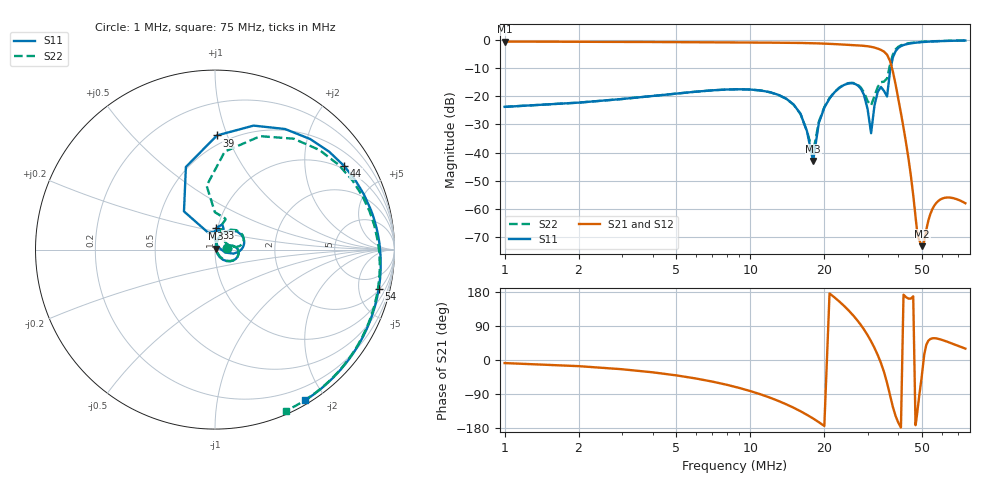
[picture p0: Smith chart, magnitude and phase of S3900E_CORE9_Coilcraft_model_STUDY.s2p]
! Simulated 50-ohm nominal data; not measured. Coilcraft 0805CS fitted passive equivalent + C0G tanD assumed.
# Hz S RI R 50
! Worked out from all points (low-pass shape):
!   277 points, 1 MHz to 75 MHz, reference 50 ohm
!   highest |S21| = -0.56 dB at 1 MHz (marker M1); lowest = -73.2 dB at 50 MHz (marker M2)
!   |S21| within 3 dB of the highest: start of sweep to 34.07 MHz
!   lowest |S11| = -43.0 dB at 18 MHz (marker M3), VSWR 1.01, Z = 50.5 + j0.514 ohm
!   |S11| at or under -10 dB: start of sweep to 37.25 MHz
!   |S22| runs from -40.1 to -0.2 dB; largest |S21 - S12| = 0
!   S11 on the Smith chart (normalised r, x): 1 MHz: 1.14, +0.02; 33 MHz: 0.99, +0.24; 39 MHz: 0.43, +0.92; 44 MHz: 0.89, +3.15; 54 MHz: 2.19, -7.93; 75 MHz: 0.04, -1.76
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1000000  0.0642 0.01  0.928 -0.1323  0.928 -0.1323  0.0642 0.01
3000000  0.087 0.0208  0.8431 -0.3813  0.8431 -0.3813  0.087 0.0208
5000000  0.1104 0.0175  0.6961 -0.5965  0.6961 -0.5965  0.1104 0.0176
9000000  0.131 -0.0258  0.2552 -0.8673  0.2552 -0.8673  0.131 -0.0252
1.5e7  0.0441 -0.0561  -0.5227 -0.7195  -0.5227 -0.7195  0.0458 -0.0542
1.7e7  0.0122 -0.0206  -0.7193 -0.5094  -0.7193 -0.5094  0.0147 -0.0189
1.8e7  0.00492 0.00509  -0.7896 -0.3797  -0.7896 -0.3797  0.00752 0.00646
1.9e7  0.00591 0.0332  -0.8367 -0.2378  -0.8367 -0.2378  0.00827 0.0343
2.2e7  0.0612 0.1008  -0.818 0.2164  -0.818 0.2164  0.0603 0.1029
2.78208e7  0.145 -0.0012  -0.098 0.7922  -0.098 0.7922  0.148 0.0286
3e7  0.0569 -0.0166  0.321 0.7049  0.321 0.7049  0.0798 0.0206
3.1e7  0.0151 0.0161  0.4935 0.5738  0.4935 0.5738  0.0476 0.05
3.3e7  0.00781 0.1203  0.6851 0.157  0.6851 0.157  0.04 0.1415
3.6e7  -0.0359 0.0925  0.2703 -0.4771  0.2703 -0.4771  -0.000873 0.2085
3.7e7  -0.1729 0.2128  -0.0207 -0.4253  -0.0207 -0.4253  -0.0467 0.3561
3.9e7  0.0108 0.6359  -0.137 -0.0866  -0.137 -0.0866  0.2523 0.6319
4.4e7  0.719 0.4666  -0.00747 0.00242  -0.00747 0.00242  0.8214 0.2983
4.7812e7  0.8862 0.1701  -0.000273 -0.000259  -0.000273 -0.000259  0.9135 -0.00216
5e7  0.918 0.0184  0.000179 -0.000125  0.000179 -0.000125  0.9158 -0.147
5.4e7  0.9126 -0.217  0.00046 0.000668  0.00046 0.000668  0.8721 -0.3645
6.1e7  0.807 -0.5177  0.000958 0.00122  0.000958 0.00122  0.7284 -0.6309
7.5e7  0.502 -0.8399  0.00109 0.00063  0.00109 0.00063  0.3983 -0.8967
